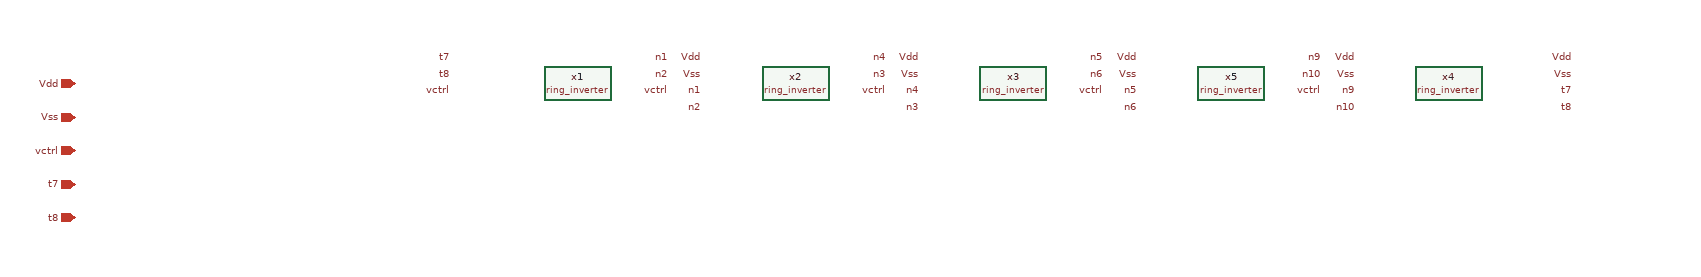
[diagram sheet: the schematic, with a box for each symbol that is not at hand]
v {xschem version=3.4.5 file_version=1.2}
G {}
K {}
V {}
S {}
E {}
C {devices/iopin.sym} -400 0 0 0 {name=p1 lab=Vdd}
C {devices/iopin.sym} -400 40 0 0 {name=p2 lab=Vss}
C {devices/iopin.sym} -400 80 0 0 {name=p3 lab=vctrl}
C {devices/iopin.sym} -400 120 0 0 {name=p4 lab=t7}
C {devices/iopin.sym} -400 160 0 0 {name=p5 lab=t8}
C {devices/lab_pin.sym} 350 -30 0 0 {name=l1 sig_type=std_logic lab=Vdd}
C {devices/lab_pin.sym} 350 -10 0 0 {name=l2 sig_type=std_logic lab=Vss}
C {devices/lab_pin.sym} 50 -30 0 0 {name=l3 sig_type=std_logic lab=t7}
C {devices/lab_pin.sym} 350 10 0 0 {name=l4 sig_type=std_logic lab=n1}
C {devices/lab_pin.sym} 50 -10 0 0 {name=l5 sig_type=std_logic lab=t8}
C {devices/lab_pin.sym} 350 30 0 0 {name=l6 sig_type=std_logic lab=n2}
C {devices/lab_pin.sym} 50 10 0 0 {name=l7 sig_type=std_logic lab=vctrl}
C {ring_inverter.sym} 200 0 0 0 {name=x1}
C {devices/lab_pin.sym} 610 -30 0 0 {name=l8 sig_type=std_logic lab=Vdd}
C {devices/lab_pin.sym} 610 -10 0 0 {name=l9 sig_type=std_logic lab=Vss}
C {devices/lab_pin.sym} 310 -30 0 0 {name=l10 sig_type=std_logic lab=n1}
C {devices/lab_pin.sym} 610 10 0 0 {name=l11 sig_type=std_logic lab=n4}
C {devices/lab_pin.sym} 310 -10 0 0 {name=l12 sig_type=std_logic lab=n2}
C {devices/lab_pin.sym} 610 30 0 0 {name=l13 sig_type=std_logic lab=n3}
C {devices/lab_pin.sym} 310 10 0 0 {name=l14 sig_type=std_logic lab=vctrl}
C {ring_inverter.sym} 460 0 0 0 {name=x2}
C {devices/lab_pin.sym} 870 -30 0 0 {name=l15 sig_type=std_logic lab=Vdd}
C {devices/lab_pin.sym} 870 -10 0 0 {name=l16 sig_type=std_logic lab=Vss}
C {devices/lab_pin.sym} 570 -30 0 0 {name=l17 sig_type=std_logic lab=n4}
C {devices/lab_pin.sym} 870 10 0 0 {name=l18 sig_type=std_logic lab=n5}
C {devices/lab_pin.sym} 570 -10 0 0 {name=l19 sig_type=std_logic lab=n3}
C {devices/lab_pin.sym} 870 30 0 0 {name=l20 sig_type=std_logic lab=n6}
C {devices/lab_pin.sym} 570 10 0 0 {name=l21 sig_type=std_logic lab=vctrl}
C {ring_inverter.sym} 720 0 0 0 {name=x3}
C {devices/lab_pin.sym} 1130 -30 0 0 {name=l22 sig_type=std_logic lab=Vdd}
C {devices/lab_pin.sym} 1130 -10 0 0 {name=l23 sig_type=std_logic lab=Vss}
C {devices/lab_pin.sym} 830 -30 0 0 {name=l24 sig_type=std_logic lab=n5}
C {devices/lab_pin.sym} 1130 10 0 0 {name=l25 sig_type=std_logic lab=n9}
C {devices/lab_pin.sym} 830 -10 0 0 {name=l26 sig_type=std_logic lab=n6}
C {devices/lab_pin.sym} 1130 30 0 0 {name=l27 sig_type=std_logic lab=n10}
C {devices/lab_pin.sym} 830 10 0 0 {name=l28 sig_type=std_logic lab=vctrl}
C {ring_inverter.sym} 980 0 0 0 {name=x5}
C {devices/lab_pin.sym} 1390 -30 0 0 {name=l29 sig_type=std_logic lab=Vdd}
C {devices/lab_pin.sym} 1390 -10 0 0 {name=l30 sig_type=std_logic lab=Vss}
C {devices/lab_pin.sym} 1090 -30 0 0 {name=l31 sig_type=std_logic lab=n9}
C {devices/lab_pin.sym} 1390 10 0 0 {name=l32 sig_type=std_logic lab=t7}
C {devices/lab_pin.sym} 1090 -10 0 0 {name=l33 sig_type=std_logic lab=n10}
C {devices/lab_pin.sym} 1390 30 0 0 {name=l34 sig_type=std_logic lab=t8}
C {devices/lab_pin.sym} 1090 10 0 0 {name=l35 sig_type=std_logic lab=vctrl}
C {ring_inverter.sym} 1240 0 0 0 {name=x4}
